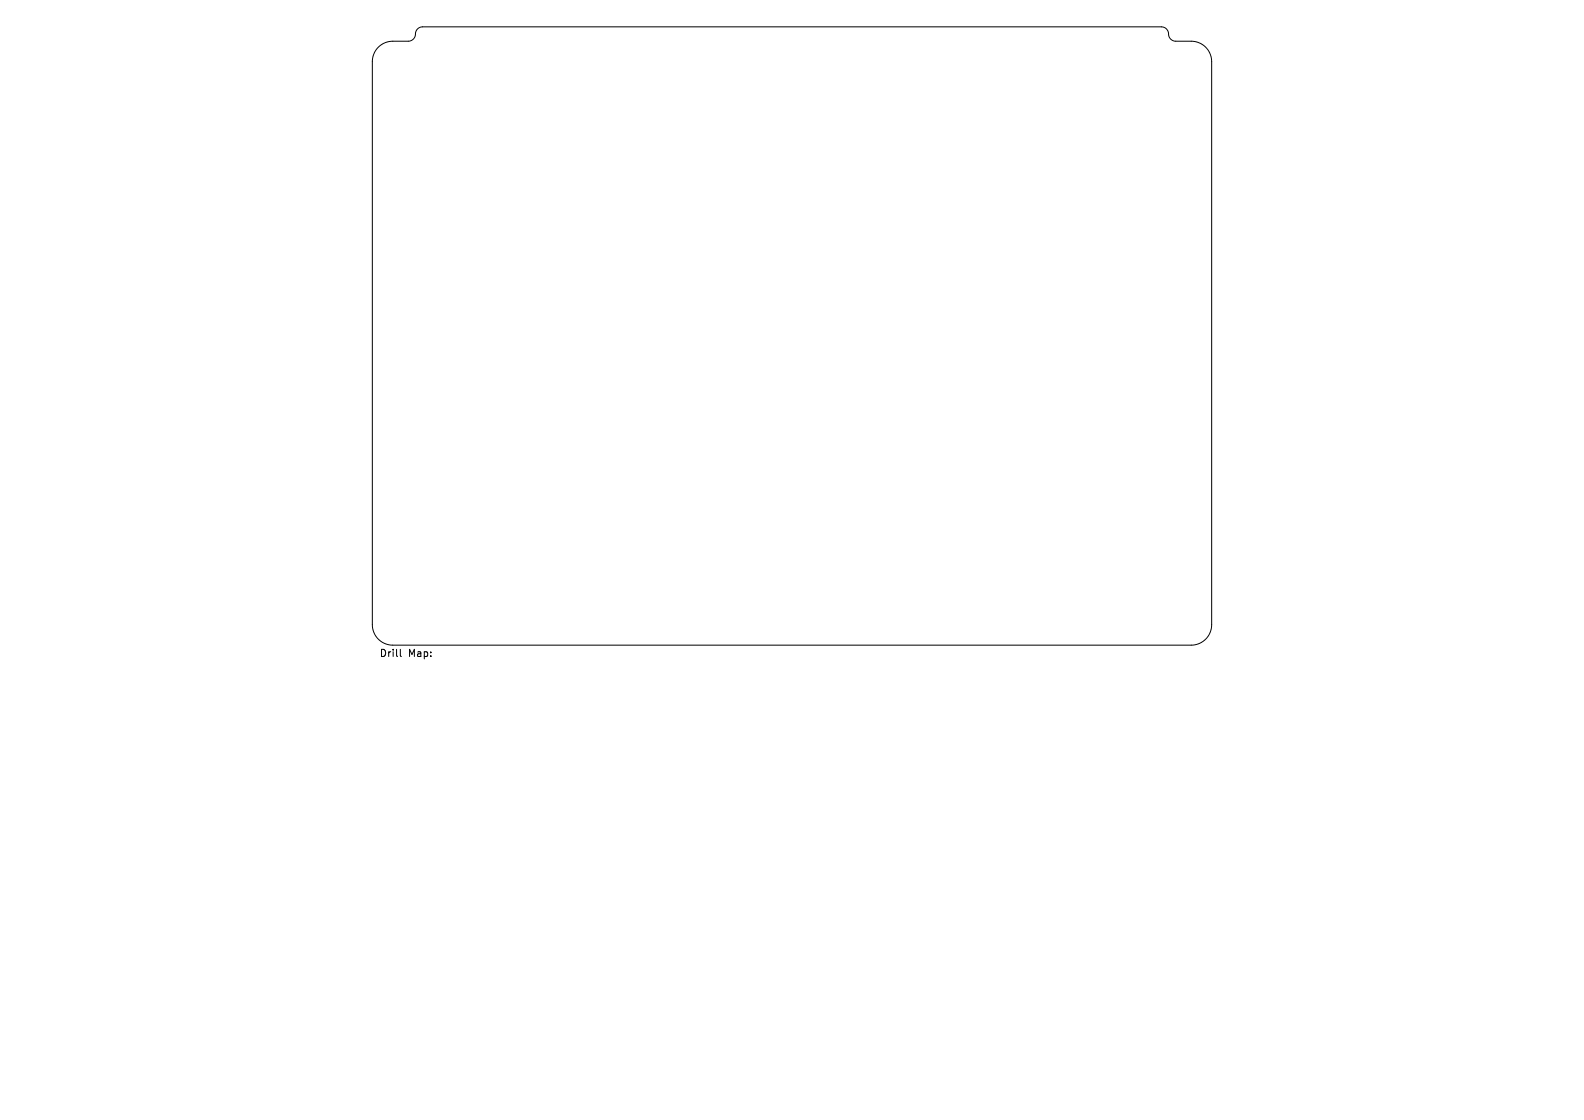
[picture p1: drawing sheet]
<svg xmlns="http://www.w3.org/2000/svg" width="297mm" height="210mm" viewBox="0 0 297 210" stroke-linecap="round" stroke-linejoin="round" font-family="sans-serif">
<defs><g id="words">
<g font-size="1.9">
<text x="71.1" y="123.4">Drill</text>
<text x="76.5" y="123.4">Map:</text>
</g>
</g></defs>
<path d="M70.9 8.8a3.8 3.8 0 0 1 2.7-1.1h2.9a1.48 1.48 0 0 0 1.4-1.7l.5-.7 .8-.3h138.6a1.47 1.47 0 0 1 1.4 1.7l.3 .6 .6 .4h3.3a3.8 3.8 0 0 1 3.8 3.9v105.5a3.8 3.8 0 0 1-3.8 3.9h-149.8a3.8 3.8 0 0 1-3.8-3.9v-105.5a3.8 3.8 0 0 1 1.1-2.8zM75.1 121.8v1.1l.2 .2" fill="none" stroke="#000" stroke-width=".19"/>
<use href="#words"/>
</svg>
